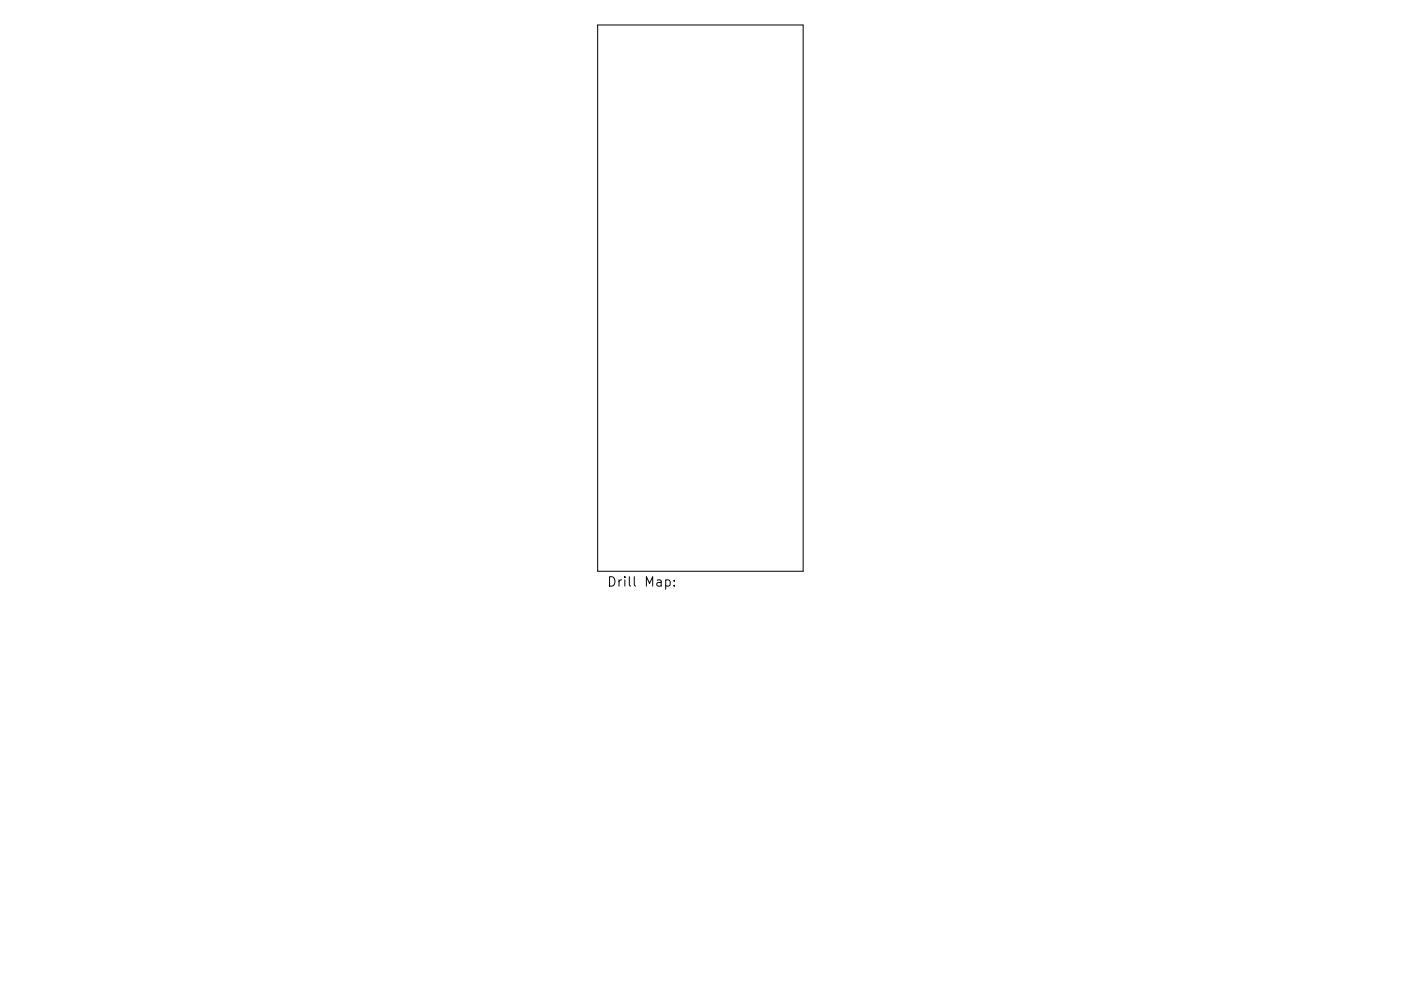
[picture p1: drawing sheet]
<svg xmlns="http://www.w3.org/2000/svg" width="297mm" height="210mm" viewBox="0 0 297 210" stroke-linecap="round" stroke-linejoin="round" font-family="sans-serif">
<defs><g id="words">
<text font-size="2.8" x="128.7" y="124.5">Drill Map:</text>
</g></defs>
<path d="M126.7 5.3h43.6v115.9h-43.6zM141.1 123.1l.6-.1 .4 .4v.6l-.2 .3h-.8M143 124.2v.2M143 123.1v.2" fill="none" stroke="#000" stroke-width=".21"/>
<use href="#words"/>
</svg>
